##
## LEF for PtnCells ;
## created by Innovus v15.23-s045_1 on Sun Mar  9 16:26:48 2025
##

VERSION 5.8 ;

BUSBITCHARS "[]" ;
DIVIDERCHAR "/" ;

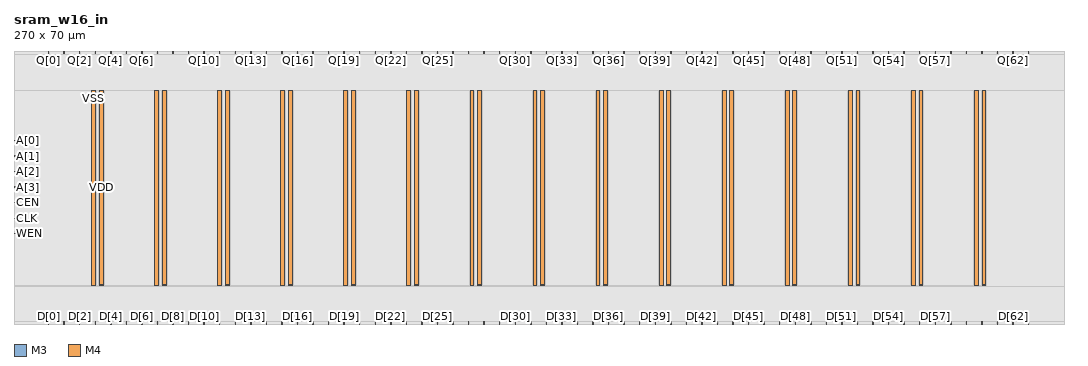
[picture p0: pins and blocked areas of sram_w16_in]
MACRO sram_w16_in
  CLASS BLOCK ;
  SIZE 270.0000 BY 70.0000 ;
  FOREIGN sram_w16_in 0.0000 0.0000 ;
  ORIGIN 0 0 ;
  SYMMETRY X Y R90 ;
  PIN CLK
    DIRECTION INPUT ;
    USE SIGNAL ;
    PORT
      LAYER M3 ;
        RECT 0.0000 27.1500 0.5200 27.2500 ;
    END
  END CLK
  PIN D[63]
    DIRECTION INPUT ;
    USE SIGNAL ;
    PORT
      LAYER M4 ;
        RECT 260.8500 0.0000 260.9500 0.5200 ;
    END
  END D[63]
  PIN D[62]
    DIRECTION INPUT ;
    USE SIGNAL ;
    PORT
      LAYER M4 ;
        RECT 256.8500 0.0000 256.9500 0.5200 ;
    END
  END D[62]
  PIN D[61]
    DIRECTION INPUT ;
    USE SIGNAL ;
    PORT
      LAYER M4 ;
        RECT 252.8500 0.0000 252.9500 0.5200 ;
    END
  END D[61]
  PIN D[60]
    DIRECTION INPUT ;
    USE SIGNAL ;
    PORT
      LAYER M4 ;
        RECT 248.8500 0.0000 248.9500 0.5200 ;
    END
  END D[60]
  PIN D[59]
    DIRECTION INPUT ;
    USE SIGNAL ;
    PORT
      LAYER M4 ;
        RECT 244.8500 0.0000 244.9500 0.5200 ;
    END
  END D[59]
  PIN D[58]
    DIRECTION INPUT ;
    USE SIGNAL ;
    PORT
      LAYER M4 ;
        RECT 240.8500 0.0000 240.9500 0.5200 ;
    END
  END D[58]
  PIN D[57]
    DIRECTION INPUT ;
    USE SIGNAL ;
    PORT
      LAYER M4 ;
        RECT 236.8500 0.0000 236.9500 0.5200 ;
    END
  END D[57]
  PIN D[56]
    DIRECTION INPUT ;
    USE SIGNAL ;
    PORT
      LAYER M4 ;
        RECT 232.8500 0.0000 232.9500 0.5200 ;
    END
  END D[56]
  PIN D[55]
    DIRECTION INPUT ;
    USE SIGNAL ;
    PORT
      LAYER M4 ;
        RECT 228.8500 0.0000 228.9500 0.5200 ;
    END
  END D[55]
  PIN D[54]
    DIRECTION INPUT ;
    USE SIGNAL ;
    PORT
      LAYER M4 ;
        RECT 224.8500 0.0000 224.9500 0.5200 ;
    END
  END D[54]
  PIN D[53]
    DIRECTION INPUT ;
    USE SIGNAL ;
    PORT
      LAYER M4 ;
        RECT 220.8500 0.0000 220.9500 0.5200 ;
    END
  END D[53]
  PIN D[52]
    DIRECTION INPUT ;
    USE SIGNAL ;
    PORT
      LAYER M4 ;
        RECT 216.8500 0.0000 216.9500 0.5200 ;
    END
  END D[52]
  PIN D[51]
    DIRECTION INPUT ;
    USE SIGNAL ;
    PORT
      LAYER M4 ;
        RECT 212.8500 0.0000 212.9500 0.5200 ;
    END
  END D[51]
  PIN D[50]
    DIRECTION INPUT ;
    USE SIGNAL ;
    PORT
      LAYER M4 ;
        RECT 208.8500 0.0000 208.9500 0.5200 ;
    END
  END D[50]
  PIN D[49]
    DIRECTION INPUT ;
    USE SIGNAL ;
    PORT
      LAYER M4 ;
        RECT 204.8500 0.0000 204.9500 0.5200 ;
    END
  END D[49]
  PIN D[48]
    DIRECTION INPUT ;
    USE SIGNAL ;
    PORT
      LAYER M4 ;
        RECT 200.8500 0.0000 200.9500 0.5200 ;
    END
  END D[48]
  PIN D[47]
    DIRECTION INPUT ;
    USE SIGNAL ;
    PORT
      LAYER M4 ;
        RECT 196.8500 0.0000 196.9500 0.5200 ;
    END
  END D[47]
  PIN D[46]
    DIRECTION INPUT ;
    USE SIGNAL ;
    PORT
      LAYER M4 ;
        RECT 192.8500 0.0000 192.9500 0.5200 ;
    END
  END D[46]
  PIN D[45]
    DIRECTION INPUT ;
    USE SIGNAL ;
    PORT
      LAYER M4 ;
        RECT 188.8500 0.0000 188.9500 0.5200 ;
    END
  END D[45]
  PIN D[44]
    DIRECTION INPUT ;
    USE SIGNAL ;
    PORT
      LAYER M4 ;
        RECT 184.8500 0.0000 184.9500 0.5200 ;
    END
  END D[44]
  PIN D[43]
    DIRECTION INPUT ;
    USE SIGNAL ;
    PORT
      LAYER M4 ;
        RECT 180.8500 0.0000 180.9500 0.5200 ;
    END
  END D[43]
  PIN D[42]
    DIRECTION INPUT ;
    USE SIGNAL ;
    PORT
      LAYER M4 ;
        RECT 176.8500 0.0000 176.9500 0.5200 ;
    END
  END D[42]
  PIN D[41]
    DIRECTION INPUT ;
    USE SIGNAL ;
    PORT
      LAYER M4 ;
        RECT 172.8500 0.0000 172.9500 0.5200 ;
    END
  END D[41]
  PIN D[40]
    DIRECTION INPUT ;
    USE SIGNAL ;
    PORT
      LAYER M4 ;
        RECT 168.8500 0.0000 168.9500 0.5200 ;
    END
  END D[40]
  PIN D[39]
    DIRECTION INPUT ;
    USE SIGNAL ;
    PORT
      LAYER M4 ;
        RECT 164.8500 0.0000 164.9500 0.5200 ;
    END
  END D[39]
  PIN D[38]
    DIRECTION INPUT ;
    USE SIGNAL ;
    PORT
      LAYER M4 ;
        RECT 160.8500 0.0000 160.9500 0.5200 ;
    END
  END D[38]
  PIN D[37]
    DIRECTION INPUT ;
    USE SIGNAL ;
    PORT
      LAYER M4 ;
        RECT 156.8500 0.0000 156.9500 0.5200 ;
    END
  END D[37]
  PIN D[36]
    DIRECTION INPUT ;
    USE SIGNAL ;
    PORT
      LAYER M4 ;
        RECT 152.8500 0.0000 152.9500 0.5200 ;
    END
  END D[36]
  PIN D[35]
    DIRECTION INPUT ;
    USE SIGNAL ;
    PORT
      LAYER M4 ;
        RECT 148.8500 0.0000 148.9500 0.5200 ;
    END
  END D[35]
  PIN D[34]
    DIRECTION INPUT ;
    USE SIGNAL ;
    PORT
      LAYER M4 ;
        RECT 144.8500 0.0000 144.9500 0.5200 ;
    END
  END D[34]
  PIN D[33]
    DIRECTION INPUT ;
    USE SIGNAL ;
    PORT
      LAYER M4 ;
        RECT 140.8500 0.0000 140.9500 0.5200 ;
    END
  END D[33]
  PIN D[32]
    DIRECTION INPUT ;
    USE SIGNAL ;
    PORT
      LAYER M4 ;
        RECT 136.8500 0.0000 136.9500 0.5200 ;
    END
  END D[32]
  PIN D[31]
    DIRECTION INPUT ;
    USE SIGNAL ;
    PORT
      LAYER M4 ;
        RECT 132.8500 0.0000 132.9500 0.5200 ;
    END
  END D[31]
  PIN D[30]
    DIRECTION INPUT ;
    USE SIGNAL ;
    PORT
      LAYER M4 ;
        RECT 128.8500 0.0000 128.9500 0.5200 ;
    END
  END D[30]
  PIN D[29]
    DIRECTION INPUT ;
    USE SIGNAL ;
    PORT
      LAYER M4 ;
        RECT 124.8500 0.0000 124.9500 0.5200 ;
    END
  END D[29]
  PIN D[28]
    DIRECTION INPUT ;
    USE SIGNAL ;
    PORT
      LAYER M4 ;
        RECT 120.8500 0.0000 120.9500 0.5200 ;
    END
  END D[28]
  PIN D[27]
    DIRECTION INPUT ;
    USE SIGNAL ;
    PORT
      LAYER M4 ;
        RECT 116.8500 0.0000 116.9500 0.5200 ;
    END
  END D[27]
  PIN D[26]
    DIRECTION INPUT ;
    USE SIGNAL ;
    PORT
      LAYER M4 ;
        RECT 112.8500 0.0000 112.9500 0.5200 ;
    END
  END D[26]
  PIN D[25]
    DIRECTION INPUT ;
    USE SIGNAL ;
    PORT
      LAYER M4 ;
        RECT 108.8500 0.0000 108.9500 0.5200 ;
    END
  END D[25]
  PIN D[24]
    DIRECTION INPUT ;
    USE SIGNAL ;
    PORT
      LAYER M4 ;
        RECT 104.8500 0.0000 104.9500 0.5200 ;
    END
  END D[24]
  PIN D[23]
    DIRECTION INPUT ;
    USE SIGNAL ;
    PORT
      LAYER M4 ;
        RECT 100.8500 0.0000 100.9500 0.5200 ;
    END
  END D[23]
  PIN D[22]
    DIRECTION INPUT ;
    USE SIGNAL ;
    PORT
      LAYER M4 ;
        RECT 96.8500 0.0000 96.9500 0.5200 ;
    END
  END D[22]
  PIN D[21]
    DIRECTION INPUT ;
    USE SIGNAL ;
    PORT
      LAYER M4 ;
        RECT 92.8500 0.0000 92.9500 0.5200 ;
    END
  END D[21]
  PIN D[20]
    DIRECTION INPUT ;
    USE SIGNAL ;
    PORT
      LAYER M4 ;
        RECT 88.8500 0.0000 88.9500 0.5200 ;
    END
  END D[20]
  PIN D[19]
    DIRECTION INPUT ;
    USE SIGNAL ;
    PORT
      LAYER M4 ;
        RECT 84.8500 0.0000 84.9500 0.5200 ;
    END
  END D[19]
  PIN D[18]
    DIRECTION INPUT ;
    USE SIGNAL ;
    PORT
      LAYER M4 ;
        RECT 80.8500 0.0000 80.9500 0.5200 ;
    END
  END D[18]
  PIN D[17]
    DIRECTION INPUT ;
    USE SIGNAL ;
    PORT
      LAYER M4 ;
        RECT 76.8500 0.0000 76.9500 0.5200 ;
    END
  END D[17]
  PIN D[16]
    DIRECTION INPUT ;
    USE SIGNAL ;
    PORT
      LAYER M4 ;
        RECT 72.8500 0.0000 72.9500 0.5200 ;
    END
  END D[16]
  PIN D[15]
    DIRECTION INPUT ;
    USE SIGNAL ;
    PORT
      LAYER M4 ;
        RECT 68.8500 0.0000 68.9500 0.5200 ;
    END
  END D[15]
  PIN D[14]
    DIRECTION INPUT ;
    USE SIGNAL ;
    PORT
      LAYER M4 ;
        RECT 64.8500 0.0000 64.9500 0.5200 ;
    END
  END D[14]
  PIN D[13]
    DIRECTION INPUT ;
    USE SIGNAL ;
    PORT
      LAYER M4 ;
        RECT 60.8500 0.0000 60.9500 0.5200 ;
    END
  END D[13]
  PIN D[12]
    DIRECTION INPUT ;
    USE SIGNAL ;
    PORT
      LAYER M4 ;
        RECT 56.8500 0.0000 56.9500 0.5200 ;
    END
  END D[12]
  PIN D[11]
    DIRECTION INPUT ;
    USE SIGNAL ;
    PORT
      LAYER M4 ;
        RECT 52.8500 0.0000 52.9500 0.5200 ;
    END
  END D[11]
  PIN D[10]
    DIRECTION INPUT ;
    USE SIGNAL ;
    PORT
      LAYER M4 ;
        RECT 48.8500 0.0000 48.9500 0.5200 ;
    END
  END D[10]
  PIN D[9]
    DIRECTION INPUT ;
    USE SIGNAL ;
    PORT
      LAYER M4 ;
        RECT 44.8500 0.0000 44.9500 0.5200 ;
    END
  END D[9]
  PIN D[8]
    DIRECTION INPUT ;
    USE SIGNAL ;
    PORT
      LAYER M4 ;
        RECT 40.8500 0.0000 40.9500 0.5200 ;
    END
  END D[8]
  PIN D[7]
    DIRECTION INPUT ;
    USE SIGNAL ;
    PORT
      LAYER M4 ;
        RECT 36.8500 0.0000 36.9500 0.5200 ;
    END
  END D[7]
  PIN D[6]
    DIRECTION INPUT ;
    USE SIGNAL ;
    PORT
      LAYER M4 ;
        RECT 32.8500 0.0000 32.9500 0.5200 ;
    END
  END D[6]
  PIN D[5]
    DIRECTION INPUT ;
    USE SIGNAL ;
    PORT
      LAYER M4 ;
        RECT 28.8500 0.0000 28.9500 0.5200 ;
    END
  END D[5]
  PIN D[4]
    DIRECTION INPUT ;
    USE SIGNAL ;
    PORT
      LAYER M4 ;
        RECT 24.8500 0.0000 24.9500 0.5200 ;
    END
  END D[4]
  PIN D[3]
    DIRECTION INPUT ;
    USE SIGNAL ;
    PORT
      LAYER M4 ;
        RECT 20.8500 0.0000 20.9500 0.5200 ;
    END
  END D[3]
  PIN D[2]
    DIRECTION INPUT ;
    USE SIGNAL ;
    PORT
      LAYER M4 ;
        RECT 16.8500 0.0000 16.9500 0.5200 ;
    END
  END D[2]
  PIN D[1]
    DIRECTION INPUT ;
    USE SIGNAL ;
    PORT
      LAYER M4 ;
        RECT 12.8500 0.0000 12.9500 0.5200 ;
    END
  END D[1]
  PIN D[0]
    DIRECTION INPUT ;
    USE SIGNAL ;
    PORT
      LAYER M4 ;
        RECT 8.8500 0.0000 8.9500 0.5200 ;
    END
  END D[0]
  PIN Q[63]
    DIRECTION OUTPUT ;
    USE SIGNAL ;
    PORT
      LAYER M4 ;
        RECT 260.8500 69.4800 260.9500 70.0000 ;
    END
  END Q[63]
  PIN Q[62]
    DIRECTION OUTPUT ;
    USE SIGNAL ;
    PORT
      LAYER M4 ;
        RECT 256.8500 69.4800 256.9500 70.0000 ;
    END
  END Q[62]
  PIN Q[61]
    DIRECTION OUTPUT ;
    USE SIGNAL ;
    PORT
      LAYER M4 ;
        RECT 252.8500 69.4800 252.9500 70.0000 ;
    END
  END Q[61]
  PIN Q[60]
    DIRECTION OUTPUT ;
    USE SIGNAL ;
    PORT
      LAYER M4 ;
        RECT 248.8500 69.4800 248.9500 70.0000 ;
    END
  END Q[60]
  PIN Q[59]
    DIRECTION OUTPUT ;
    USE SIGNAL ;
    PORT
      LAYER M4 ;
        RECT 244.8500 69.4800 244.9500 70.0000 ;
    END
  END Q[59]
  PIN Q[58]
    DIRECTION OUTPUT ;
    USE SIGNAL ;
    PORT
      LAYER M4 ;
        RECT 240.8500 69.4800 240.9500 70.0000 ;
    END
  END Q[58]
  PIN Q[57]
    DIRECTION OUTPUT ;
    USE SIGNAL ;
    PORT
      LAYER M4 ;
        RECT 236.8500 69.4800 236.9500 70.0000 ;
    END
  END Q[57]
  PIN Q[56]
    DIRECTION OUTPUT ;
    USE SIGNAL ;
    PORT
      LAYER M4 ;
        RECT 232.8500 69.4800 232.9500 70.0000 ;
    END
  END Q[56]
  PIN Q[55]
    DIRECTION OUTPUT ;
    USE SIGNAL ;
    PORT
      LAYER M4 ;
        RECT 228.8500 69.4800 228.9500 70.0000 ;
    END
  END Q[55]
  PIN Q[54]
    DIRECTION OUTPUT ;
    USE SIGNAL ;
    PORT
      LAYER M4 ;
        RECT 224.8500 69.4800 224.9500 70.0000 ;
    END
  END Q[54]
  PIN Q[53]
    DIRECTION OUTPUT ;
    USE SIGNAL ;
    PORT
      LAYER M4 ;
        RECT 220.8500 69.4800 220.9500 70.0000 ;
    END
  END Q[53]
  PIN Q[52]
    DIRECTION OUTPUT ;
    USE SIGNAL ;
    PORT
      LAYER M4 ;
        RECT 216.8500 69.4800 216.9500 70.0000 ;
    END
  END Q[52]
  PIN Q[51]
    DIRECTION OUTPUT ;
    USE SIGNAL ;
    PORT
      LAYER M4 ;
        RECT 212.8500 69.4800 212.9500 70.0000 ;
    END
  END Q[51]
  PIN Q[50]
    DIRECTION OUTPUT ;
    USE SIGNAL ;
    PORT
      LAYER M4 ;
        RECT 208.8500 69.4800 208.9500 70.0000 ;
    END
  END Q[50]
  PIN Q[49]
    DIRECTION OUTPUT ;
    USE SIGNAL ;
    PORT
      LAYER M4 ;
        RECT 204.8500 69.4800 204.9500 70.0000 ;
    END
  END Q[49]
  PIN Q[48]
    DIRECTION OUTPUT ;
    USE SIGNAL ;
    PORT
      LAYER M4 ;
        RECT 200.8500 69.4800 200.9500 70.0000 ;
    END
  END Q[48]
  PIN Q[47]
    DIRECTION OUTPUT ;
    USE SIGNAL ;
    PORT
      LAYER M4 ;
        RECT 196.8500 69.4800 196.9500 70.0000 ;
    END
  END Q[47]
  PIN Q[46]
    DIRECTION OUTPUT ;
    USE SIGNAL ;
    PORT
      LAYER M4 ;
        RECT 192.8500 69.4800 192.9500 70.0000 ;
    END
  END Q[46]
  PIN Q[45]
    DIRECTION OUTPUT ;
    USE SIGNAL ;
    PORT
      LAYER M4 ;
        RECT 188.8500 69.4800 188.9500 70.0000 ;
    END
  END Q[45]
  PIN Q[44]
    DIRECTION OUTPUT ;
    USE SIGNAL ;
    PORT
      LAYER M4 ;
        RECT 184.8500 69.4800 184.9500 70.0000 ;
    END
  END Q[44]
  PIN Q[43]
    DIRECTION OUTPUT ;
    USE SIGNAL ;
    PORT
      LAYER M4 ;
        RECT 180.8500 69.4800 180.9500 70.0000 ;
    END
  END Q[43]
  PIN Q[42]
    DIRECTION OUTPUT ;
    USE SIGNAL ;
    PORT
      LAYER M4 ;
        RECT 176.8500 69.4800 176.9500 70.0000 ;
    END
  END Q[42]
  PIN Q[41]
    DIRECTION OUTPUT ;
    USE SIGNAL ;
    PORT
      LAYER M4 ;
        RECT 172.8500 69.4800 172.9500 70.0000 ;
    END
  END Q[41]
  PIN Q[40]
    DIRECTION OUTPUT ;
    USE SIGNAL ;
    PORT
      LAYER M4 ;
        RECT 168.8500 69.4800 168.9500 70.0000 ;
    END
  END Q[40]
  PIN Q[39]
    DIRECTION OUTPUT ;
    USE SIGNAL ;
    PORT
      LAYER M4 ;
        RECT 164.8500 69.4800 164.9500 70.0000 ;
    END
  END Q[39]
  PIN Q[38]
    DIRECTION OUTPUT ;
    USE SIGNAL ;
    PORT
      LAYER M4 ;
        RECT 160.8500 69.4800 160.9500 70.0000 ;
    END
  END Q[38]
  PIN Q[37]
    DIRECTION OUTPUT ;
    USE SIGNAL ;
    PORT
      LAYER M4 ;
        RECT 156.8500 69.4800 156.9500 70.0000 ;
    END
  END Q[37]
  PIN Q[36]
    DIRECTION OUTPUT ;
    USE SIGNAL ;
    PORT
      LAYER M4 ;
        RECT 152.8500 69.4800 152.9500 70.0000 ;
    END
  END Q[36]
  PIN Q[35]
    DIRECTION OUTPUT ;
    USE SIGNAL ;
    PORT
      LAYER M4 ;
        RECT 148.8500 69.4800 148.9500 70.0000 ;
    END
  END Q[35]
  PIN Q[34]
    DIRECTION OUTPUT ;
    USE SIGNAL ;
    PORT
      LAYER M4 ;
        RECT 144.8500 69.4800 144.9500 70.0000 ;
    END
  END Q[34]
  PIN Q[33]
    DIRECTION OUTPUT ;
    USE SIGNAL ;
    PORT
      LAYER M4 ;
        RECT 140.8500 69.4800 140.9500 70.0000 ;
    END
  END Q[33]
  PIN Q[32]
    DIRECTION OUTPUT ;
    USE SIGNAL ;
    PORT
      LAYER M4 ;
        RECT 136.8500 69.4800 136.9500 70.0000 ;
    END
  END Q[32]
  PIN Q[31]
    DIRECTION OUTPUT ;
    USE SIGNAL ;
    PORT
      LAYER M4 ;
        RECT 132.8500 69.4800 132.9500 70.0000 ;
    END
  END Q[31]
  PIN Q[30]
    DIRECTION OUTPUT ;
    USE SIGNAL ;
    PORT
      LAYER M4 ;
        RECT 128.8500 69.4800 128.9500 70.0000 ;
    END
  END Q[30]
  PIN Q[29]
    DIRECTION OUTPUT ;
    USE SIGNAL ;
    PORT
      LAYER M4 ;
        RECT 124.8500 69.4800 124.9500 70.0000 ;
    END
  END Q[29]
  PIN Q[28]
    DIRECTION OUTPUT ;
    USE SIGNAL ;
    PORT
      LAYER M4 ;
        RECT 120.8500 69.4800 120.9500 70.0000 ;
    END
  END Q[28]
  PIN Q[27]
    DIRECTION OUTPUT ;
    USE SIGNAL ;
    PORT
      LAYER M4 ;
        RECT 116.8500 69.4800 116.9500 70.0000 ;
    END
  END Q[27]
  PIN Q[26]
    DIRECTION OUTPUT ;
    USE SIGNAL ;
    PORT
      LAYER M4 ;
        RECT 112.8500 69.4800 112.9500 70.0000 ;
    END
  END Q[26]
  PIN Q[25]
    DIRECTION OUTPUT ;
    USE SIGNAL ;
    PORT
      LAYER M4 ;
        RECT 108.8500 69.4800 108.9500 70.0000 ;
    END
  END Q[25]
  PIN Q[24]
    DIRECTION OUTPUT ;
    USE SIGNAL ;
    PORT
      LAYER M4 ;
        RECT 104.8500 69.4800 104.9500 70.0000 ;
    END
  END Q[24]
  PIN Q[23]
    DIRECTION OUTPUT ;
    USE SIGNAL ;
    PORT
      LAYER M4 ;
        RECT 100.8500 69.4800 100.9500 70.0000 ;
    END
  END Q[23]
  PIN Q[22]
    DIRECTION OUTPUT ;
    USE SIGNAL ;
    PORT
      LAYER M4 ;
        RECT 96.8500 69.4800 96.9500 70.0000 ;
    END
  END Q[22]
  PIN Q[21]
    DIRECTION OUTPUT ;
    USE SIGNAL ;
    PORT
      LAYER M4 ;
        RECT 92.8500 69.4800 92.9500 70.0000 ;
    END
  END Q[21]
  PIN Q[20]
    DIRECTION OUTPUT ;
    USE SIGNAL ;
    PORT
      LAYER M4 ;
        RECT 88.8500 69.4800 88.9500 70.0000 ;
    END
  END Q[20]
  PIN Q[19]
    DIRECTION OUTPUT ;
    USE SIGNAL ;
    PORT
      LAYER M4 ;
        RECT 84.8500 69.4800 84.9500 70.0000 ;
    END
  END Q[19]
  PIN Q[18]
    DIRECTION OUTPUT ;
    USE SIGNAL ;
    PORT
      LAYER M4 ;
        RECT 80.8500 69.4800 80.9500 70.0000 ;
    END
  END Q[18]
  PIN Q[17]
    DIRECTION OUTPUT ;
    USE SIGNAL ;
    PORT
      LAYER M4 ;
        RECT 76.8500 69.4800 76.9500 70.0000 ;
    END
  END Q[17]
  PIN Q[16]
    DIRECTION OUTPUT ;
    USE SIGNAL ;
    PORT
      LAYER M4 ;
        RECT 72.8500 69.4800 72.9500 70.0000 ;
    END
  END Q[16]
  PIN Q[15]
    DIRECTION OUTPUT ;
    USE SIGNAL ;
    PORT
      LAYER M4 ;
        RECT 68.8500 69.4800 68.9500 70.0000 ;
    END
  END Q[15]
  PIN Q[14]
    DIRECTION OUTPUT ;
    USE SIGNAL ;
    PORT
      LAYER M4 ;
        RECT 64.8500 69.4800 64.9500 70.0000 ;
    END
  END Q[14]
  PIN Q[13]
    DIRECTION OUTPUT ;
    USE SIGNAL ;
    PORT
      LAYER M4 ;
        RECT 60.8500 69.4800 60.9500 70.0000 ;
    END
  END Q[13]
  PIN Q[12]
    DIRECTION OUTPUT ;
    USE SIGNAL ;
    PORT
      LAYER M4 ;
        RECT 56.8500 69.4800 56.9500 70.0000 ;
    END
  END Q[12]
  PIN Q[11]
    DIRECTION OUTPUT ;
    USE SIGNAL ;
    PORT
      LAYER M4 ;
        RECT 52.8500 69.4800 52.9500 70.0000 ;
    END
  END Q[11]
  PIN Q[10]
    DIRECTION OUTPUT ;
    USE SIGNAL ;
    PORT
      LAYER M4 ;
        RECT 48.8500 69.4800 48.9500 70.0000 ;
    END
  END Q[10]
  PIN Q[9]
    DIRECTION OUTPUT ;
    USE SIGNAL ;
    PORT
      LAYER M4 ;
        RECT 44.8500 69.4800 44.9500 70.0000 ;
    END
  END Q[9]
  PIN Q[8]
    DIRECTION OUTPUT ;
    USE SIGNAL ;
    PORT
      LAYER M4 ;
        RECT 40.8500 69.4800 40.9500 70.0000 ;
    END
  END Q[8]
  PIN Q[7]
    DIRECTION OUTPUT ;
    USE SIGNAL ;
    PORT
      LAYER M4 ;
        RECT 36.8500 69.4800 36.9500 70.0000 ;
    END
  END Q[7]
  PIN Q[6]
    DIRECTION OUTPUT ;
    USE SIGNAL ;
    PORT
      LAYER M4 ;
        RECT 32.8500 69.4800 32.9500 70.0000 ;
    END
  END Q[6]
  PIN Q[5]
    DIRECTION OUTPUT ;
    USE SIGNAL ;
    PORT
      LAYER M4 ;
        RECT 28.8500 69.4800 28.9500 70.0000 ;
    END
  END Q[5]
  PIN Q[4]
    DIRECTION OUTPUT ;
    USE SIGNAL ;
    PORT
      LAYER M4 ;
        RECT 24.8500 69.4800 24.9500 70.0000 ;
    END
  END Q[4]
  PIN Q[3]
    DIRECTION OUTPUT ;
    USE SIGNAL ;
    PORT
      LAYER M4 ;
        RECT 20.8500 69.4800 20.9500 70.0000 ;
    END
  END Q[3]
  PIN Q[2]
    DIRECTION OUTPUT ;
    USE SIGNAL ;
    PORT
      LAYER M4 ;
        RECT 16.8500 69.4800 16.9500 70.0000 ;
    END
  END Q[2]
  PIN Q[1]
    DIRECTION OUTPUT ;
    USE SIGNAL ;
    PORT
      LAYER M4 ;
        RECT 12.8500 69.4800 12.9500 70.0000 ;
    END
  END Q[1]
  PIN Q[0]
    DIRECTION OUTPUT ;
    USE SIGNAL ;
    PORT
      LAYER M4 ;
        RECT 8.8500 69.4800 8.9500 70.0000 ;
    END
  END Q[0]
  PIN CEN
    DIRECTION INPUT ;
    USE SIGNAL ;
    PORT
      LAYER M3 ;
        RECT 0.0000 31.1500 0.5200 31.2500 ;
    END
  END CEN
  PIN WEN
    DIRECTION INPUT ;
    USE SIGNAL ;
    PORT
      LAYER M3 ;
        RECT 0.0000 23.1500 0.5200 23.2500 ;
    END
  END WEN
  PIN A[3]
    DIRECTION INPUT ;
    USE SIGNAL ;
    PORT
      LAYER M3 ;
        RECT 0.0000 35.1500 0.5200 35.2500 ;
    END
  END A[3]
  PIN A[2]
    DIRECTION INPUT ;
    USE SIGNAL ;
    PORT
      LAYER M3 ;
        RECT 0.0000 39.1500 0.5200 39.2500 ;
    END
  END A[2]
  PIN A[1]
    DIRECTION INPUT ;
    USE SIGNAL ;
    PORT
      LAYER M3 ;
        RECT 0.0000 43.1500 0.5200 43.2500 ;
    END
  END A[1]
  PIN A[0]
    DIRECTION INPUT ;
    USE SIGNAL ;
    PORT
      LAYER M3 ;
        RECT 0.0000 47.1500 0.5200 47.2500 ;
    END
  END A[0]
  PIN VSS
    DIRECTION INOUT ;
    USE GROUND ;

# P/G power stripe data as pin
    PORT
      LAYER M4 ;
        RECT 20.0000 10.0000 21.0000 60.0000 ;
        RECT 36.2100 10.0000 37.2100 60.0000 ;
        RECT 52.4200 10.0000 53.4200 60.0000 ;
        RECT 68.6300 10.0000 69.6300 60.0000 ;
        RECT 84.8400 10.0000 85.8400 60.0000 ;
        RECT 101.0500 10.0000 102.0500 60.0000 ;
        RECT 117.2600 10.0000 118.2600 60.0000 ;
        RECT 133.4700 10.0000 134.4700 60.0000 ;
        RECT 149.6800 10.0000 150.6800 60.0000 ;
        RECT 165.8900 10.0000 166.8900 60.0000 ;
        RECT 182.1000 10.0000 183.1000 60.0000 ;
        RECT 198.3100 10.0000 199.3100 60.0000 ;
        RECT 214.5200 10.0000 215.5200 60.0000 ;
        RECT 230.7300 10.0000 231.7300 60.0000 ;
        RECT 246.9400 10.0000 247.9400 60.0000 ;
    END
# end of P/G power stripe data as pin

  END VSS
  PIN VDD
    DIRECTION INOUT ;
    USE POWER ;

# P/G power stripe data as pin
    PORT
      LAYER M4 ;
        RECT 22.0000 10.0000 23.0000 60.0000 ;
        RECT 38.2100 10.0000 39.2100 60.0000 ;
        RECT 54.4200 10.0000 55.4200 60.0000 ;
        RECT 70.6300 10.0000 71.6300 60.0000 ;
        RECT 86.8400 10.0000 87.8400 60.0000 ;
        RECT 103.0500 10.0000 104.0500 60.0000 ;
        RECT 119.2600 10.0000 120.2600 60.0000 ;
        RECT 135.4700 10.0000 136.4700 60.0000 ;
        RECT 151.6800 10.0000 152.6800 60.0000 ;
        RECT 167.8900 10.0000 168.8900 60.0000 ;
        RECT 184.1000 10.0000 185.1000 60.0000 ;
        RECT 200.3100 10.0000 201.3100 60.0000 ;
        RECT 216.5200 10.0000 217.5200 60.0000 ;
        RECT 232.7300 10.0000 233.7300 60.0000 ;
        RECT 248.9400 10.0000 249.9400 60.0000 ;
        RECT 22.0000 9.8350 23.0000 10.1650 ;
        RECT 38.2100 9.8350 39.2100 10.1650 ;
        RECT 54.4200 9.8350 55.4200 10.1650 ;
        RECT 70.6300 9.8350 71.6300 10.1650 ;
        RECT 86.8400 9.8350 87.8400 10.1650 ;
        RECT 103.0500 9.8350 104.0500 10.1650 ;
        RECT 119.2600 9.8350 120.2600 10.1650 ;
        RECT 167.8900 9.8350 168.8900 10.1650 ;
        RECT 151.6800 9.8350 152.6800 10.1650 ;
        RECT 135.4700 9.8350 136.4700 10.1650 ;
        RECT 184.1000 9.8350 185.1000 10.1650 ;
        RECT 200.3100 9.8350 201.3100 10.1650 ;
        RECT 216.5200 9.8350 217.5200 10.1650 ;
        RECT 232.7300 9.8350 233.7300 10.1650 ;
        RECT 248.9400 9.8350 249.9400 10.1650 ;
    END
# end of P/G power stripe data as pin

  END VDD
  OBS
    LAYER M1 ;
      RECT 0.0000 0.0000 270.0000 70.0000 ;
    LAYER M2 ;
      RECT 0.0000 0.0000 270.0000 70.0000 ;
    LAYER M3 ;
      RECT 0.0000 47.3500 270.0000 70.0000 ;
      RECT 0.6200 47.0500 270.0000 47.3500 ;
      RECT 0.0000 43.3500 270.0000 47.0500 ;
      RECT 0.6200 43.0500 270.0000 43.3500 ;
      RECT 0.0000 39.3500 270.0000 43.0500 ;
      RECT 0.6200 39.0500 270.0000 39.3500 ;
      RECT 0.0000 35.3500 270.0000 39.0500 ;
      RECT 0.6200 35.0500 270.0000 35.3500 ;
      RECT 0.0000 31.3500 270.0000 35.0500 ;
      RECT 0.6200 31.0500 270.0000 31.3500 ;
      RECT 0.0000 27.3500 270.0000 31.0500 ;
      RECT 0.6200 27.0500 270.0000 27.3500 ;
      RECT 0.0000 23.3500 270.0000 27.0500 ;
      RECT 0.6200 23.0500 270.0000 23.3500 ;
      RECT 0.0000 0.0000 270.0000 23.0500 ;
    LAYER M4 ;
      RECT 261.0500 69.3800 270.0000 70.0000 ;
      RECT 257.0500 69.3800 260.7500 70.0000 ;
      RECT 253.0500 69.3800 256.7500 70.0000 ;
      RECT 249.0500 69.3800 252.7500 70.0000 ;
      RECT 245.0500 69.3800 248.7500 70.0000 ;
      RECT 241.0500 69.3800 244.7500 70.0000 ;
      RECT 237.0500 69.3800 240.7500 70.0000 ;
      RECT 233.0500 69.3800 236.7500 70.0000 ;
      RECT 229.0500 69.3800 232.7500 70.0000 ;
      RECT 225.0500 69.3800 228.7500 70.0000 ;
      RECT 221.0500 69.3800 224.7500 70.0000 ;
      RECT 217.0500 69.3800 220.7500 70.0000 ;
      RECT 213.0500 69.3800 216.7500 70.0000 ;
      RECT 209.0500 69.3800 212.7500 70.0000 ;
      RECT 205.0500 69.3800 208.7500 70.0000 ;
      RECT 201.0500 69.3800 204.7500 70.0000 ;
      RECT 197.0500 69.3800 200.7500 70.0000 ;
      RECT 193.0500 69.3800 196.7500 70.0000 ;
      RECT 189.0500 69.3800 192.7500 70.0000 ;
      RECT 185.0500 69.3800 188.7500 70.0000 ;
      RECT 181.0500 69.3800 184.7500 70.0000 ;
      RECT 177.0500 69.3800 180.7500 70.0000 ;
      RECT 173.0500 69.3800 176.7500 70.0000 ;
      RECT 169.0500 69.3800 172.7500 70.0000 ;
      RECT 165.0500 69.3800 168.7500 70.0000 ;
      RECT 161.0500 69.3800 164.7500 70.0000 ;
      RECT 157.0500 69.3800 160.7500 70.0000 ;
      RECT 153.0500 69.3800 156.7500 70.0000 ;
      RECT 149.0500 69.3800 152.7500 70.0000 ;
      RECT 145.0500 69.3800 148.7500 70.0000 ;
      RECT 141.0500 69.3800 144.7500 70.0000 ;
      RECT 137.0500 69.3800 140.7500 70.0000 ;
      RECT 133.0500 69.3800 136.7500 70.0000 ;
      RECT 129.0500 69.3800 132.7500 70.0000 ;
      RECT 125.0500 69.3800 128.7500 70.0000 ;
      RECT 121.0500 69.3800 124.7500 70.0000 ;
      RECT 117.0500 69.3800 120.7500 70.0000 ;
      RECT 113.0500 69.3800 116.7500 70.0000 ;
      RECT 109.0500 69.3800 112.7500 70.0000 ;
      RECT 105.0500 69.3800 108.7500 70.0000 ;
      RECT 101.0500 69.3800 104.7500 70.0000 ;
      RECT 97.0500 69.3800 100.7500 70.0000 ;
      RECT 93.0500 69.3800 96.7500 70.0000 ;
      RECT 89.0500 69.3800 92.7500 70.0000 ;
      RECT 85.0500 69.3800 88.7500 70.0000 ;
      RECT 81.0500 69.3800 84.7500 70.0000 ;
      RECT 77.0500 69.3800 80.7500 70.0000 ;
      RECT 73.0500 69.3800 76.7500 70.0000 ;
      RECT 69.0500 69.3800 72.7500 70.0000 ;
      RECT 65.0500 69.3800 68.7500 70.0000 ;
      RECT 61.0500 69.3800 64.7500 70.0000 ;
      RECT 57.0500 69.3800 60.7500 70.0000 ;
      RECT 53.0500 69.3800 56.7500 70.0000 ;
      RECT 49.0500 69.3800 52.7500 70.0000 ;
      RECT 45.0500 69.3800 48.7500 70.0000 ;
      RECT 41.0500 69.3800 44.7500 70.0000 ;
      RECT 37.0500 69.3800 40.7500 70.0000 ;
      RECT 33.0500 69.3800 36.7500 70.0000 ;
      RECT 29.0500 69.3800 32.7500 70.0000 ;
      RECT 25.0500 69.3800 28.7500 70.0000 ;
      RECT 21.0500 69.3800 24.7500 70.0000 ;
      RECT 17.0500 69.3800 20.7500 70.0000 ;
      RECT 13.0500 69.3800 16.7500 70.0000 ;
      RECT 9.0500 69.3800 12.7500 70.0000 ;
      RECT 0.0000 69.3800 8.7500 70.0000 ;
      RECT 0.0000 60.1600 270.0000 69.3800 ;
      RECT 248.1000 9.8400 248.7800 60.1600 ;
      RECT 233.8900 9.8400 246.7800 60.1600 ;
      RECT 231.8900 9.8400 232.5700 60.1600 ;
      RECT 217.6800 9.8400 230.5700 60.1600 ;
      RECT 215.6800 9.8400 216.3600 60.1600 ;
      RECT 201.4700 9.8400 214.3600 60.1600 ;
      RECT 199.4700 9.8400 200.1500 60.1600 ;
      RECT 185.2600 9.8400 198.1500 60.1600 ;
      RECT 183.2600 9.8400 183.9400 60.1600 ;
      RECT 169.0500 9.8400 181.9400 60.1600 ;
      RECT 167.0500 9.8400 167.7300 60.1600 ;
      RECT 152.8400 9.8400 165.7300 60.1600 ;
      RECT 150.8400 9.8400 151.5200 60.1600 ;
      RECT 136.6300 9.8400 149.5200 60.1600 ;
      RECT 134.6300 9.8400 135.3100 60.1600 ;
      RECT 120.4200 9.8400 133.3100 60.1600 ;
      RECT 118.4200 9.8400 119.1000 60.1600 ;
      RECT 104.2100 9.8400 117.1000 60.1600 ;
      RECT 102.2100 9.8400 102.8900 60.1600 ;
      RECT 88.0000 9.8400 100.8900 60.1600 ;
      RECT 86.0000 9.8400 86.6800 60.1600 ;
      RECT 71.7900 9.8400 84.6800 60.1600 ;
      RECT 69.7900 9.8400 70.4700 60.1600 ;
      RECT 55.5800 9.8400 68.4700 60.1600 ;
      RECT 53.5800 9.8400 54.2600 60.1600 ;
      RECT 39.3700 9.8400 52.2600 60.1600 ;
      RECT 37.3700 9.8400 38.0500 60.1600 ;
      RECT 23.1600 9.8400 36.0500 60.1600 ;
      RECT 21.1600 9.8400 21.8400 60.1600 ;
      RECT 0.0000 9.8400 19.8400 60.1600 ;
      RECT 250.1000 9.6750 270.0000 60.1600 ;
      RECT 233.8900 9.6750 248.7800 9.8400 ;
      RECT 217.6800 9.6750 232.5700 9.8400 ;
      RECT 201.4700 9.6750 216.3600 9.8400 ;
      RECT 185.2600 9.6750 200.1500 9.8400 ;
      RECT 169.0500 9.6750 183.9400 9.8400 ;
      RECT 152.8400 9.6750 167.7300 9.8400 ;
      RECT 136.6300 9.6750 151.5200 9.8400 ;
      RECT 120.4200 9.6750 135.3100 9.8400 ;
      RECT 104.2100 9.6750 119.1000 9.8400 ;
      RECT 88.0000 9.6750 102.8900 9.8400 ;
      RECT 71.7900 9.6750 86.6800 9.8400 ;
      RECT 55.5800 9.6750 70.4700 9.8400 ;
      RECT 39.3700 9.6750 54.2600 9.8400 ;
      RECT 23.1600 9.6750 38.0500 9.8400 ;
      RECT 0.0000 9.6750 21.8400 9.8400 ;
      RECT 0.0000 0.6200 270.0000 9.6750 ;
      RECT 261.0500 0.0000 270.0000 0.6200 ;
      RECT 257.0500 0.0000 260.7500 0.6200 ;
      RECT 253.0500 0.0000 256.7500 0.6200 ;
      RECT 249.0500 0.0000 252.7500 0.6200 ;
      RECT 245.0500 0.0000 248.7500 0.6200 ;
      RECT 241.0500 0.0000 244.7500 0.6200 ;
      RECT 237.0500 0.0000 240.7500 0.6200 ;
      RECT 233.0500 0.0000 236.7500 0.6200 ;
      RECT 229.0500 0.0000 232.7500 0.6200 ;
      RECT 225.0500 0.0000 228.7500 0.6200 ;
      RECT 221.0500 0.0000 224.7500 0.6200 ;
      RECT 217.0500 0.0000 220.7500 0.6200 ;
      RECT 213.0500 0.0000 216.7500 0.6200 ;
      RECT 209.0500 0.0000 212.7500 0.6200 ;
      RECT 205.0500 0.0000 208.7500 0.6200 ;
      RECT 201.0500 0.0000 204.7500 0.6200 ;
      RECT 197.0500 0.0000 200.7500 0.6200 ;
      RECT 193.0500 0.0000 196.7500 0.6200 ;
      RECT 189.0500 0.0000 192.7500 0.6200 ;
      RECT 185.0500 0.0000 188.7500 0.6200 ;
      RECT 181.0500 0.0000 184.7500 0.6200 ;
      RECT 177.0500 0.0000 180.7500 0.6200 ;
      RECT 173.0500 0.0000 176.7500 0.6200 ;
      RECT 169.0500 0.0000 172.7500 0.6200 ;
      RECT 165.0500 0.0000 168.7500 0.6200 ;
      RECT 161.0500 0.0000 164.7500 0.6200 ;
      RECT 157.0500 0.0000 160.7500 0.6200 ;
      RECT 153.0500 0.0000 156.7500 0.6200 ;
      RECT 149.0500 0.0000 152.7500 0.6200 ;
      RECT 145.0500 0.0000 148.7500 0.6200 ;
      RECT 141.0500 0.0000 144.7500 0.6200 ;
      RECT 137.0500 0.0000 140.7500 0.6200 ;
      RECT 133.0500 0.0000 136.7500 0.6200 ;
      RECT 129.0500 0.0000 132.7500 0.6200 ;
      RECT 125.0500 0.0000 128.7500 0.6200 ;
      RECT 121.0500 0.0000 124.7500 0.6200 ;
      RECT 117.0500 0.0000 120.7500 0.6200 ;
      RECT 113.0500 0.0000 116.7500 0.6200 ;
      RECT 109.0500 0.0000 112.7500 0.6200 ;
      RECT 105.0500 0.0000 108.7500 0.6200 ;
      RECT 101.0500 0.0000 104.7500 0.6200 ;
      RECT 97.0500 0.0000 100.7500 0.6200 ;
      RECT 93.0500 0.0000 96.7500 0.6200 ;
      RECT 89.0500 0.0000 92.7500 0.6200 ;
      RECT 85.0500 0.0000 88.7500 0.6200 ;
      RECT 81.0500 0.0000 84.7500 0.6200 ;
      RECT 77.0500 0.0000 80.7500 0.6200 ;
      RECT 73.0500 0.0000 76.7500 0.6200 ;
      RECT 69.0500 0.0000 72.7500 0.6200 ;
      RECT 65.0500 0.0000 68.7500 0.6200 ;
      RECT 61.0500 0.0000 64.7500 0.6200 ;
      RECT 57.0500 0.0000 60.7500 0.6200 ;
      RECT 53.0500 0.0000 56.7500 0.6200 ;
      RECT 49.0500 0.0000 52.7500 0.6200 ;
      RECT 45.0500 0.0000 48.7500 0.6200 ;
      RECT 41.0500 0.0000 44.7500 0.6200 ;
      RECT 37.0500 0.0000 40.7500 0.6200 ;
      RECT 33.0500 0.0000 36.7500 0.6200 ;
      RECT 29.0500 0.0000 32.7500 0.6200 ;
      RECT 25.0500 0.0000 28.7500 0.6200 ;
      RECT 21.0500 0.0000 24.7500 0.6200 ;
      RECT 17.0500 0.0000 20.7500 0.6200 ;
      RECT 13.0500 0.0000 16.7500 0.6200 ;
      RECT 9.0500 0.0000 12.7500 0.6200 ;
      RECT 0.0000 0.0000 8.7500 0.6200 ;
  END
END sram_w16_in

END LIBRARY
